# Generated by FakeRAM 2.0
VERSION 5.7 ;
BUSBITCHARS "[]" ;
PROPERTYDEFINITIONS
  MACRO width INTEGER ;
  MACRO depth INTEGER ;
  MACRO banks INTEGER ;
END PROPERTYDEFINITIONS
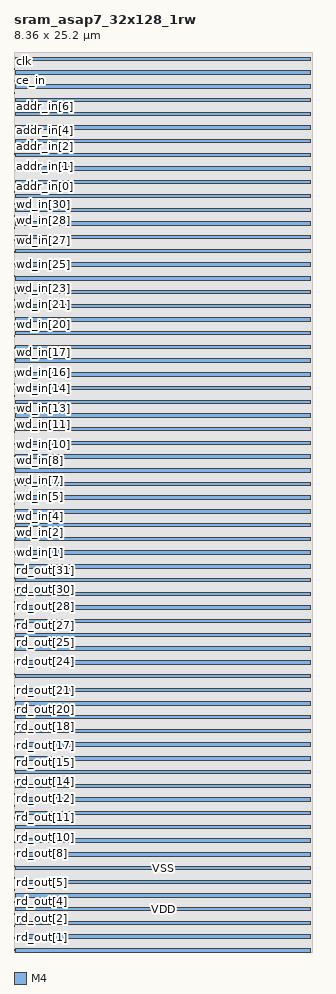
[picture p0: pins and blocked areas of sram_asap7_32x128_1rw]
MACRO sram_asap7_32x128_1rw
  PROPERTY width 32 ;
  PROPERTY depth 128 ;
  PROPERTY banks 1 ;
  FOREIGN sram_asap7_32x128_1rw 0 0 ;
  SYMMETRY X Y R90 ;
  SIZE 8.360 BY 25.200 ;
  CLASS BLOCK ;
  PIN rd_out[0]
    DIRECTION OUTPUT ;
    USE SIGNAL ;
    SHAPE ABUTMENT ;
    PORT
      LAYER M4 ;
      RECT 0.000 0.048 0.024 0.072 ;
    END
  END rd_out[0]
  PIN rd_out[1]
    DIRECTION OUTPUT ;
    USE SIGNAL ;
    SHAPE ABUTMENT ;
    PORT
      LAYER M4 ;
      RECT 0.000 0.384 0.024 0.408 ;
    END
  END rd_out[1]
  PIN rd_out[2]
    DIRECTION OUTPUT ;
    USE SIGNAL ;
    SHAPE ABUTMENT ;
    PORT
      LAYER M4 ;
      RECT 0.000 0.720 0.024 0.744 ;
    END
  END rd_out[2]
  PIN rd_out[3]
    DIRECTION OUTPUT ;
    USE SIGNAL ;
    SHAPE ABUTMENT ;
    PORT
      LAYER M4 ;
      RECT 0.000 1.056 0.024 1.080 ;
    END
  END rd_out[3]
  PIN rd_out[4]
    DIRECTION OUTPUT ;
    USE SIGNAL ;
    SHAPE ABUTMENT ;
    PORT
      LAYER M4 ;
      RECT 0.000 1.392 0.024 1.416 ;
    END
  END rd_out[4]
  PIN rd_out[5]
    DIRECTION OUTPUT ;
    USE SIGNAL ;
    SHAPE ABUTMENT ;
    PORT
      LAYER M4 ;
      RECT 0.000 1.728 0.024 1.752 ;
    END
  END rd_out[5]
  PIN rd_out[6]
    DIRECTION OUTPUT ;
    USE SIGNAL ;
    SHAPE ABUTMENT ;
    PORT
      LAYER M4 ;
      RECT 0.000 2.064 0.024 2.088 ;
    END
  END rd_out[6]
  PIN rd_out[7]
    DIRECTION OUTPUT ;
    USE SIGNAL ;
    SHAPE ABUTMENT ;
    PORT
      LAYER M4 ;
      RECT 0.000 2.400 0.024 2.424 ;
    END
  END rd_out[7]
  PIN rd_out[8]
    DIRECTION OUTPUT ;
    USE SIGNAL ;
    SHAPE ABUTMENT ;
    PORT
      LAYER M4 ;
      RECT 0.000 2.736 0.024 2.760 ;
    END
  END rd_out[8]
  PIN rd_out[9]
    DIRECTION OUTPUT ;
    USE SIGNAL ;
    SHAPE ABUTMENT ;
    PORT
      LAYER M4 ;
      RECT 0.000 3.072 0.024 3.096 ;
    END
  END rd_out[9]
  PIN rd_out[10]
    DIRECTION OUTPUT ;
    USE SIGNAL ;
    SHAPE ABUTMENT ;
    PORT
      LAYER M4 ;
      RECT 0.000 3.408 0.024 3.432 ;
    END
  END rd_out[10]
  PIN rd_out[11]
    DIRECTION OUTPUT ;
    USE SIGNAL ;
    SHAPE ABUTMENT ;
    PORT
      LAYER M4 ;
      RECT 0.000 3.744 0.024 3.768 ;
    END
  END rd_out[11]
  PIN rd_out[12]
    DIRECTION OUTPUT ;
    USE SIGNAL ;
    SHAPE ABUTMENT ;
    PORT
      LAYER M4 ;
      RECT 0.000 4.080 0.024 4.104 ;
    END
  END rd_out[12]
  PIN rd_out[13]
    DIRECTION OUTPUT ;
    USE SIGNAL ;
    SHAPE ABUTMENT ;
    PORT
      LAYER M4 ;
      RECT 0.000 4.416 0.024 4.440 ;
    END
  END rd_out[13]
  PIN rd_out[14]
    DIRECTION OUTPUT ;
    USE SIGNAL ;
    SHAPE ABUTMENT ;
    PORT
      LAYER M4 ;
      RECT 0.000 4.752 0.024 4.776 ;
    END
  END rd_out[14]
  PIN rd_out[15]
    DIRECTION OUTPUT ;
    USE SIGNAL ;
    SHAPE ABUTMENT ;
    PORT
      LAYER M4 ;
      RECT 0.000 5.088 0.024 5.112 ;
    END
  END rd_out[15]
  PIN rd_out[16]
    DIRECTION OUTPUT ;
    USE SIGNAL ;
    SHAPE ABUTMENT ;
    PORT
      LAYER M4 ;
      RECT 0.000 5.424 0.024 5.448 ;
    END
  END rd_out[16]
  PIN rd_out[17]
    DIRECTION OUTPUT ;
    USE SIGNAL ;
    SHAPE ABUTMENT ;
    PORT
      LAYER M4 ;
      RECT 0.000 5.760 0.024 5.784 ;
    END
  END rd_out[17]
  PIN rd_out[18]
    DIRECTION OUTPUT ;
    USE SIGNAL ;
    SHAPE ABUTMENT ;
    PORT
      LAYER M4 ;
      RECT 0.000 6.096 0.024 6.120 ;
    END
  END rd_out[18]
  PIN rd_out[19]
    DIRECTION OUTPUT ;
    USE SIGNAL ;
    SHAPE ABUTMENT ;
    PORT
      LAYER M4 ;
      RECT 0.000 6.432 0.024 6.456 ;
    END
  END rd_out[19]
  PIN rd_out[20]
    DIRECTION OUTPUT ;
    USE SIGNAL ;
    SHAPE ABUTMENT ;
    PORT
      LAYER M4 ;
      RECT 0.000 6.768 0.024 6.792 ;
    END
  END rd_out[20]
  PIN rd_out[21]
    DIRECTION OUTPUT ;
    USE SIGNAL ;
    SHAPE ABUTMENT ;
    PORT
      LAYER M4 ;
      RECT 0.000 7.104 0.024 7.128 ;
    END
  END rd_out[21]
  PIN rd_out[22]
    DIRECTION OUTPUT ;
    USE SIGNAL ;
    SHAPE ABUTMENT ;
    PORT
      LAYER M4 ;
      RECT 0.000 7.440 0.024 7.464 ;
    END
  END rd_out[22]
  PIN rd_out[23]
    DIRECTION OUTPUT ;
    USE SIGNAL ;
    SHAPE ABUTMENT ;
    PORT
      LAYER M4 ;
      RECT 0.000 7.776 0.024 7.800 ;
    END
  END rd_out[23]
  PIN rd_out[24]
    DIRECTION OUTPUT ;
    USE SIGNAL ;
    SHAPE ABUTMENT ;
    PORT
      LAYER M4 ;
      RECT 0.000 8.112 0.024 8.136 ;
    END
  END rd_out[24]
  PIN rd_out[25]
    DIRECTION OUTPUT ;
    USE SIGNAL ;
    SHAPE ABUTMENT ;
    PORT
      LAYER M4 ;
      RECT 0.000 8.448 0.024 8.472 ;
    END
  END rd_out[25]
  PIN rd_out[26]
    DIRECTION OUTPUT ;
    USE SIGNAL ;
    SHAPE ABUTMENT ;
    PORT
      LAYER M4 ;
      RECT 0.000 8.784 0.024 8.808 ;
    END
  END rd_out[26]
  PIN rd_out[27]
    DIRECTION OUTPUT ;
    USE SIGNAL ;
    SHAPE ABUTMENT ;
    PORT
      LAYER M4 ;
      RECT 0.000 9.120 0.024 9.144 ;
    END
  END rd_out[27]
  PIN rd_out[28]
    DIRECTION OUTPUT ;
    USE SIGNAL ;
    SHAPE ABUTMENT ;
    PORT
      LAYER M4 ;
      RECT 0.000 9.456 0.024 9.480 ;
    END
  END rd_out[28]
  PIN rd_out[29]
    DIRECTION OUTPUT ;
    USE SIGNAL ;
    SHAPE ABUTMENT ;
    PORT
      LAYER M4 ;
      RECT 0.000 9.792 0.024 9.816 ;
    END
  END rd_out[29]
  PIN rd_out[30]
    DIRECTION OUTPUT ;
    USE SIGNAL ;
    SHAPE ABUTMENT ;
    PORT
      LAYER M4 ;
      RECT 0.000 10.128 0.024 10.152 ;
    END
  END rd_out[30]
  PIN rd_out[31]
    DIRECTION OUTPUT ;
    USE SIGNAL ;
    SHAPE ABUTMENT ;
    PORT
      LAYER M4 ;
      RECT 0.000 10.464 0.024 10.488 ;
    END
  END rd_out[31]
  PIN wd_in[0]
    DIRECTION INPUT ;
    USE SIGNAL ;
    SHAPE ABUTMENT ;
    PORT
      LAYER M4 ;
      RECT 0.000 10.848 0.024 10.872 ;
    END
  END wd_in[0]
  PIN wd_in[1]
    DIRECTION INPUT ;
    USE SIGNAL ;
    SHAPE ABUTMENT ;
    PORT
      LAYER M4 ;
      RECT 0.000 11.184 0.024 11.208 ;
    END
  END wd_in[1]
  PIN wd_in[2]
    DIRECTION INPUT ;
    USE SIGNAL ;
    SHAPE ABUTMENT ;
    PORT
      LAYER M4 ;
      RECT 0.000 11.520 0.024 11.544 ;
    END
  END wd_in[2]
  PIN wd_in[3]
    DIRECTION INPUT ;
    USE SIGNAL ;
    SHAPE ABUTMENT ;
    PORT
      LAYER M4 ;
      RECT 0.000 11.856 0.024 11.880 ;
    END
  END wd_in[3]
  PIN wd_in[4]
    DIRECTION INPUT ;
    USE SIGNAL ;
    SHAPE ABUTMENT ;
    PORT
      LAYER M4 ;
      RECT 0.000 12.192 0.024 12.216 ;
    END
  END wd_in[4]
  PIN wd_in[5]
    DIRECTION INPUT ;
    USE SIGNAL ;
    SHAPE ABUTMENT ;
    PORT
      LAYER M4 ;
      RECT 0.000 12.528 0.024 12.552 ;
    END
  END wd_in[5]
  PIN wd_in[6]
    DIRECTION INPUT ;
    USE SIGNAL ;
    SHAPE ABUTMENT ;
    PORT
      LAYER M4 ;
      RECT 0.000 12.864 0.024 12.888 ;
    END
  END wd_in[6]
  PIN wd_in[7]
    DIRECTION INPUT ;
    USE SIGNAL ;
    SHAPE ABUTMENT ;
    PORT
      LAYER M4 ;
      RECT 0.000 13.200 0.024 13.224 ;
    END
  END wd_in[7]
  PIN wd_in[8]
    DIRECTION INPUT ;
    USE SIGNAL ;
    SHAPE ABUTMENT ;
    PORT
      LAYER M4 ;
      RECT 0.000 13.536 0.024 13.560 ;
    END
  END wd_in[8]
  PIN wd_in[9]
    DIRECTION INPUT ;
    USE SIGNAL ;
    SHAPE ABUTMENT ;
    PORT
      LAYER M4 ;
      RECT 0.000 13.872 0.024 13.896 ;
    END
  END wd_in[9]
  PIN wd_in[10]
    DIRECTION INPUT ;
    USE SIGNAL ;
    SHAPE ABUTMENT ;
    PORT
      LAYER M4 ;
      RECT 0.000 14.208 0.024 14.232 ;
    END
  END wd_in[10]
  PIN wd_in[11]
    DIRECTION INPUT ;
    USE SIGNAL ;
    SHAPE ABUTMENT ;
    PORT
      LAYER M4 ;
      RECT 0.000 14.544 0.024 14.568 ;
    END
  END wd_in[11]
  PIN wd_in[12]
    DIRECTION INPUT ;
    USE SIGNAL ;
    SHAPE ABUTMENT ;
    PORT
      LAYER M4 ;
      RECT 0.000 14.880 0.024 14.904 ;
    END
  END wd_in[12]
  PIN wd_in[13]
    DIRECTION INPUT ;
    USE SIGNAL ;
    SHAPE ABUTMENT ;
    PORT
      LAYER M4 ;
      RECT 0.000 15.216 0.024 15.240 ;
    END
  END wd_in[13]
  PIN wd_in[14]
    DIRECTION INPUT ;
    USE SIGNAL ;
    SHAPE ABUTMENT ;
    PORT
      LAYER M4 ;
      RECT 0.000 15.552 0.024 15.576 ;
    END
  END wd_in[14]
  PIN wd_in[15]
    DIRECTION INPUT ;
    USE SIGNAL ;
    SHAPE ABUTMENT ;
    PORT
      LAYER M4 ;
      RECT 0.000 15.888 0.024 15.912 ;
    END
  END wd_in[15]
  PIN wd_in[16]
    DIRECTION INPUT ;
    USE SIGNAL ;
    SHAPE ABUTMENT ;
    PORT
      LAYER M4 ;
      RECT 0.000 16.224 0.024 16.248 ;
    END
  END wd_in[16]
  PIN wd_in[17]
    DIRECTION INPUT ;
    USE SIGNAL ;
    SHAPE ABUTMENT ;
    PORT
      LAYER M4 ;
      RECT 0.000 16.560 0.024 16.584 ;
    END
  END wd_in[17]
  PIN wd_in[18]
    DIRECTION INPUT ;
    USE SIGNAL ;
    SHAPE ABUTMENT ;
    PORT
      LAYER M4 ;
      RECT 0.000 16.896 0.024 16.920 ;
    END
  END wd_in[18]
  PIN wd_in[19]
    DIRECTION INPUT ;
    USE SIGNAL ;
    SHAPE ABUTMENT ;
    PORT
      LAYER M4 ;
      RECT 0.000 17.232 0.024 17.256 ;
    END
  END wd_in[19]
  PIN wd_in[20]
    DIRECTION INPUT ;
    USE SIGNAL ;
    SHAPE ABUTMENT ;
    PORT
      LAYER M4 ;
      RECT 0.000 17.568 0.024 17.592 ;
    END
  END wd_in[20]
  PIN wd_in[21]
    DIRECTION INPUT ;
    USE SIGNAL ;
    SHAPE ABUTMENT ;
    PORT
      LAYER M4 ;
      RECT 0.000 17.904 0.024 17.928 ;
    END
  END wd_in[21]
  PIN wd_in[22]
    DIRECTION INPUT ;
    USE SIGNAL ;
    SHAPE ABUTMENT ;
    PORT
      LAYER M4 ;
      RECT 0.000 18.240 0.024 18.264 ;
    END
  END wd_in[22]
  PIN wd_in[23]
    DIRECTION INPUT ;
    USE SIGNAL ;
    SHAPE ABUTMENT ;
    PORT
      LAYER M4 ;
      RECT 0.000 18.576 0.024 18.600 ;
    END
  END wd_in[23]
  PIN wd_in[24]
    DIRECTION INPUT ;
    USE SIGNAL ;
    SHAPE ABUTMENT ;
    PORT
      LAYER M4 ;
      RECT 0.000 18.912 0.024 18.936 ;
    END
  END wd_in[24]
  PIN wd_in[25]
    DIRECTION INPUT ;
    USE SIGNAL ;
    SHAPE ABUTMENT ;
    PORT
      LAYER M4 ;
      RECT 0.000 19.248 0.024 19.272 ;
    END
  END wd_in[25]
  PIN wd_in[26]
    DIRECTION INPUT ;
    USE SIGNAL ;
    SHAPE ABUTMENT ;
    PORT
      LAYER M4 ;
      RECT 0.000 19.584 0.024 19.608 ;
    END
  END wd_in[26]
  PIN wd_in[27]
    DIRECTION INPUT ;
    USE SIGNAL ;
    SHAPE ABUTMENT ;
    PORT
      LAYER M4 ;
      RECT 0.000 19.920 0.024 19.944 ;
    END
  END wd_in[27]
  PIN wd_in[28]
    DIRECTION INPUT ;
    USE SIGNAL ;
    SHAPE ABUTMENT ;
    PORT
      LAYER M4 ;
      RECT 0.000 20.256 0.024 20.280 ;
    END
  END wd_in[28]
  PIN wd_in[29]
    DIRECTION INPUT ;
    USE SIGNAL ;
    SHAPE ABUTMENT ;
    PORT
      LAYER M4 ;
      RECT 0.000 20.592 0.024 20.616 ;
    END
  END wd_in[29]
  PIN wd_in[30]
    DIRECTION INPUT ;
    USE SIGNAL ;
    SHAPE ABUTMENT ;
    PORT
      LAYER M4 ;
      RECT 0.000 20.928 0.024 20.952 ;
    END
  END wd_in[30]
  PIN wd_in[31]
    DIRECTION INPUT ;
    USE SIGNAL ;
    SHAPE ABUTMENT ;
    PORT
      LAYER M4 ;
      RECT 0.000 21.264 0.024 21.288 ;
    END
  END wd_in[31]
  PIN addr_in[0]
    DIRECTION INPUT ;
    USE SIGNAL ;
    SHAPE ABUTMENT ;
    PORT
      LAYER M4 ;
      RECT 0.000 21.648 0.024 21.672 ;
    END
  END addr_in[0]
  PIN addr_in[1]
    DIRECTION INPUT ;
    USE SIGNAL ;
    SHAPE ABUTMENT ;
    PORT
      LAYER M4 ;
      RECT 0.000 21.984 0.024 22.008 ;
    END
  END addr_in[1]
  PIN addr_in[2]
    DIRECTION INPUT ;
    USE SIGNAL ;
    SHAPE ABUTMENT ;
    PORT
      LAYER M4 ;
      RECT 0.000 22.320 0.024 22.344 ;
    END
  END addr_in[2]
  PIN addr_in[3]
    DIRECTION INPUT ;
    USE SIGNAL ;
    SHAPE ABUTMENT ;
    PORT
      LAYER M4 ;
      RECT 0.000 22.656 0.024 22.680 ;
    END
  END addr_in[3]
  PIN addr_in[4]
    DIRECTION INPUT ;
    USE SIGNAL ;
    SHAPE ABUTMENT ;
    PORT
      LAYER M4 ;
      RECT 0.000 22.992 0.024 23.016 ;
    END
  END addr_in[4]
  PIN addr_in[5]
    DIRECTION INPUT ;
    USE SIGNAL ;
    SHAPE ABUTMENT ;
    PORT
      LAYER M4 ;
      RECT 0.000 23.328 0.024 23.352 ;
    END
  END addr_in[5]
  PIN addr_in[6]
    DIRECTION INPUT ;
    USE SIGNAL ;
    SHAPE ABUTMENT ;
    PORT
      LAYER M4 ;
      RECT 0.000 23.664 0.024 23.688 ;
    END
  END addr_in[6]
  PIN we_in
    DIRECTION INPUT ;
    USE SIGNAL ;
    SHAPE ABUTMENT ;
    PORT
      LAYER M4 ;
      RECT 0.000 24.048 0.024 24.072 ;
    END
  END we_in
  PIN ce_in
    DIRECTION INPUT ;
    USE SIGNAL ;
    SHAPE ABUTMENT ;
    PORT
      LAYER M4 ;
      RECT 0.000 24.384 0.024 24.408 ;
    END
  END ce_in
  PIN clk
    DIRECTION INPUT ;
    USE SIGNAL ;
    SHAPE ABUTMENT ;
    PORT
      LAYER M4 ;
      RECT 0.000 24.720 0.024 24.744 ;
    END
  END clk
  PIN VSS
    DIRECTION INOUT ;
    USE GROUND ;
    PORT
      LAYER M4 ;
      RECT 0.048 0.000 8.312 0.096 ;
      RECT 0.048 0.768 8.312 0.864 ;
      RECT 0.048 1.536 8.312 1.632 ;
      RECT 0.048 2.304 8.312 2.400 ;
      RECT 0.048 3.072 8.312 3.168 ;
      RECT 0.048 3.840 8.312 3.936 ;
      RECT 0.048 4.608 8.312 4.704 ;
      RECT 0.048 5.376 8.312 5.472 ;
      RECT 0.048 6.144 8.312 6.240 ;
      RECT 0.048 6.912 8.312 7.008 ;
      RECT 0.048 7.680 8.312 7.776 ;
      RECT 0.048 8.448 8.312 8.544 ;
      RECT 0.048 9.216 8.312 9.312 ;
      RECT 0.048 9.984 8.312 10.080 ;
      RECT 0.048 10.752 8.312 10.848 ;
      RECT 0.048 11.520 8.312 11.616 ;
      RECT 0.048 12.288 8.312 12.384 ;
      RECT 0.048 13.056 8.312 13.152 ;
      RECT 0.048 13.824 8.312 13.920 ;
      RECT 0.048 14.592 8.312 14.688 ;
      RECT 0.048 15.360 8.312 15.456 ;
      RECT 0.048 16.128 8.312 16.224 ;
      RECT 0.048 16.896 8.312 16.992 ;
      RECT 0.048 17.664 8.312 17.760 ;
      RECT 0.048 18.432 8.312 18.528 ;
      RECT 0.048 19.200 8.312 19.296 ;
      RECT 0.048 19.968 8.312 20.064 ;
      RECT 0.048 20.736 8.312 20.832 ;
      RECT 0.048 21.504 8.312 21.600 ;
      RECT 0.048 22.272 8.312 22.368 ;
      RECT 0.048 23.040 8.312 23.136 ;
      RECT 0.048 23.808 8.312 23.904 ;
      RECT 0.048 24.576 8.312 24.672 ;
    END
  END VSS
  PIN VDD
    DIRECTION INOUT ;
    USE POWER ;
    PORT
      LAYER M4 ;
      RECT 0.048 0.384 8.312 0.480 ;
      RECT 0.048 1.152 8.312 1.248 ;
      RECT 0.048 1.920 8.312 2.016 ;
      RECT 0.048 2.688 8.312 2.784 ;
      RECT 0.048 3.456 8.312 3.552 ;
      RECT 0.048 4.224 8.312 4.320 ;
      RECT 0.048 4.992 8.312 5.088 ;
      RECT 0.048 5.760 8.312 5.856 ;
      RECT 0.048 6.528 8.312 6.624 ;
      RECT 0.048 7.296 8.312 7.392 ;
      RECT 0.048 8.064 8.312 8.160 ;
      RECT 0.048 8.832 8.312 8.928 ;
      RECT 0.048 9.600 8.312 9.696 ;
      RECT 0.048 10.368 8.312 10.464 ;
      RECT 0.048 11.136 8.312 11.232 ;
      RECT 0.048 11.904 8.312 12.000 ;
      RECT 0.048 12.672 8.312 12.768 ;
      RECT 0.048 13.440 8.312 13.536 ;
      RECT 0.048 14.208 8.312 14.304 ;
      RECT 0.048 14.976 8.312 15.072 ;
      RECT 0.048 15.744 8.312 15.840 ;
      RECT 0.048 16.512 8.312 16.608 ;
      RECT 0.048 17.280 8.312 17.376 ;
      RECT 0.048 18.048 8.312 18.144 ;
      RECT 0.048 18.816 8.312 18.912 ;
      RECT 0.048 19.584 8.312 19.680 ;
      RECT 0.048 20.352 8.312 20.448 ;
      RECT 0.048 21.120 8.312 21.216 ;
      RECT 0.048 21.888 8.312 21.984 ;
      RECT 0.048 22.656 8.312 22.752 ;
      RECT 0.048 23.424 8.312 23.520 ;
      RECT 0.048 24.192 8.312 24.288 ;
      RECT 0.048 24.960 8.312 25.056 ;
    END
  END VDD
  OBS
    LAYER M1 ;
    RECT 0 0 8.360 25.200 ;
    LAYER M2 ;
    RECT 0 0 8.360 25.200 ;
    LAYER M3 ;
    RECT 0 0 8.360 25.200 ;
    LAYER M4 ;
    RECT 0 0 8.360 25.200 ;
  END
END sram_asap7_32x128_1rw

END LIBRARY
